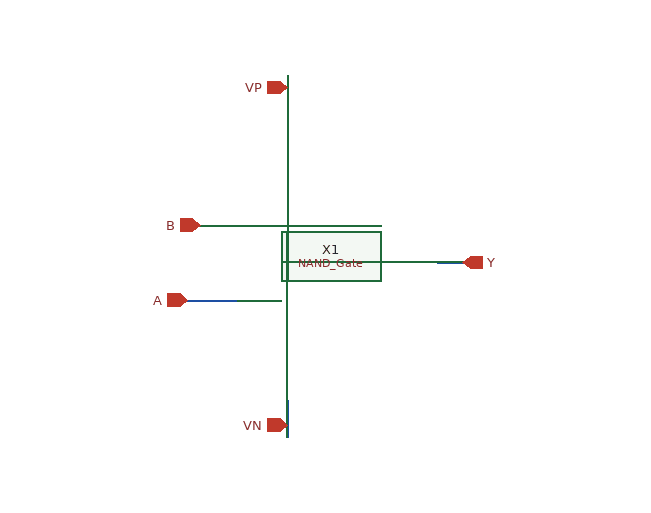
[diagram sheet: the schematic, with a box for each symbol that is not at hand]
v {xschem version=2.9.9 file_version=1.2 }
G {}
K {}
V {}
S {}
E {}
N 170 -260 200 -260 { lab=B}
N 200 -260 210 -260 { lab=B}
N 170 -200 210 -200 { lab=A}
N 250 -120 250 -90 { lab=VN}
N 250 -380 250 -340 { lab=VP}
N 370 -230 400 -230 {}
C {/home/madvlsi/Documents/Mini_Project_1/NAND_Gate.sym} 110 -180 0 0 {name=X1}
C {devices/ipin.sym} 180 -260 0 0 {name=p1 lab=B}
C {devices/ipin.sym} 170 -200 0 0 {name=p2 lab=A}
C {devices/iopin.sym} 250 -100 1 0 {name=p3 lab=VN}
C {devices/iopin.sym} 250 -370 3 0 {name=p4 lab=VP}
C {devices/opin.sym} 390 -230 0 0 {name=p5 lab=Y}
